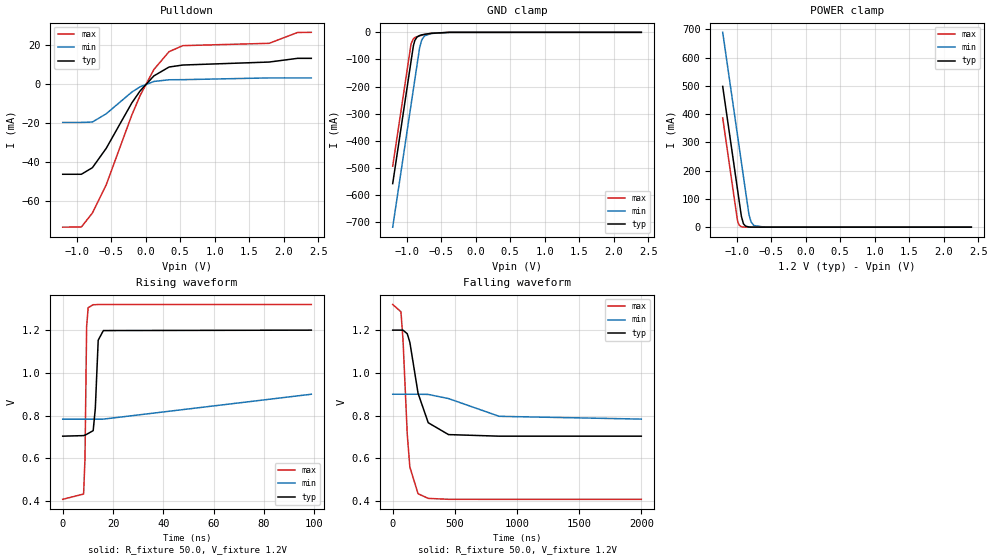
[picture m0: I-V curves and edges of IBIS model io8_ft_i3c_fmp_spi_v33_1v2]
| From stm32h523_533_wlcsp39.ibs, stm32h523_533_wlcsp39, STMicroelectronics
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[Model]   io8_ft_i3c_fmp_spi_v33_1v2
Model_type I/O_open_drain
Polarity   Non-Inverting
Enable   Active-Low
| CAP_THRESHOLD on pad IOFT is "UDTCAPC" :
| Rising=20.0% of vddiom   Falling=80.0% of vddiom
| C_comp min and max val. don't necessarily correlate with the min and max pvt
| but are the smallest and greatest pad capacitance found.
| var   typ   min   max
C_comp   3.39510pF  3.36975pF  3.42670pF
|C_comp_pulldown   3.39510pF  3.36975pF  3.42670pF
Vinl = 450.0mV
Vinh = 660.0mV
Vmeas = 600.0mV   | Reference voltage for timing measurements
Cref  = 50.0pF   | Timing specification test load capacitance value
Rref  = 1.0MOhm   | Timing specification test load resistance value
Vref  = 660.0mV   | Timing specification test load voltage
[Model Spec]
| TIME_THRESHOLD on pin ZII2CV11 is "CMOS" :
| Rising=40.0% of vdd   Falling=60.0% of vdd
Vinl 437.80000mV 335.80000mV 479.80000mV
Vinh 728.20000mV 529.20000mV 807.20000mV
| variable   typ   min   max
[Temperature Range] 25.0 125.0 -40.0
| variable   typ   min   max
[Voltage Range] 1.2V 900.0mV 1.32V
| variable   typ   min   max
[POWER Clamp Reference] 1.2V 900.0mV 1.32V
| variable   typ   min   max
[GND Clamp Reference] 0V 0V 0V
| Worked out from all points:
|   slope of the pulldown table from 0 to 0.18 V, typ, clamps not added: 30.6 ohm
|   GND clamp passes 1 mA (typ) near -0.52 V on its own axis
|   POWER clamp passes 1 mA (typ) near -0.84 V on its own axis
|   rising waveform, R_fixture 50.0, V_fixture 1.2V: 20-80 % time 1.09ns typ, 3.4ns min, 533ps max; typ from 0.704 V to 1.2 V
|   falling waveform, R_fixture 50.0, V_fixture 1.2V: 20-80 % time 103ns typ, 289ns min, 48.7ns max; typ from 1.2 V to 0.704 V
[POWER Clamp]
-1.2V     497.8mA    689.2mA    386.5mA
-990mV    140.8mA    332.2mA    29.53mA
-980mV    123.8mA    315.2mA    17.95mA
-960mV    89.81mA    281.2mA    6.634mA
-930mV    38.81mA    230.2mA    1.49mA
-900mV    12.07mA    179.2mA    334.8uA
-870mV    3.756mA    128.2mA    75.22uA
-820mV    536.4uA    44.98mA    6.246uA
-790mV    166.9uA    18.76mA    1.403uA
-750mV    35.18uA    5.846mA    191.8nA
-590mV    70.09nA    55uA       165.5pA
2.4V      0A         0A         0A
[GND Clamp]
-1.2V     -558.2mA   -719mA     -494.1mA
-940mV    -116.2mA   -277mA     -52.06mA
-930mV    -99.19mA   -260mA     -39.94mA
-900mV    -49.1mA    -209mA     -23.76mA
-880mV    -30.14mA   -175mA     -19.6mA
-850mV    -17.82mA   -124mA     -16.09mA
-810mV    -11.73mA   -56.78mA   -12.91mA
-780mV    -9.444mA   -28.21mA   -10.92mA
-740mV    -7.291mA   -13.16mA   -8.574mA
-640mV    -3.573mA   -4.171mA   -3.954mA
-380mV    -61.75uA   -230.3uA   -20.32uA
2.4V      3.863nA    718.4nA    150.6pA
| variable   typ   min   max
[Pullup Reference] 1.2V 900.0mV 1.32V
| variable   typ   min   max
[Pulldown Reference] 0V 0V 0V
[Pulldown]
-1.2V     -46.17mA   -19.61mA   -73.27mA
-930mV    -46.17mA   -19.61mA   -73.18mA
-770mV    -42.8mA    -19.4mA    -66.04mA
-570mV    -32.88mA   -15.17mA   -51.58mA
-200mV    -9.658mA   -4.081mA   -15.89mA
-80mV     -3.488mA   -1.363mA   -5.887mA
120mV     4.232mA    1.386mA    7.501mA
340mV     8.782mA    2.249mA    16.66mA
540mV     9.805mA    2.304mA    19.74mA
1.79V     11.33mA    3.204mA    20.93mA
2.2V      13.23mA    3.204mA    26.48mA
2.4V      13.23mA    3.204mA    26.56mA
[Ramp]
dV/dt_r 297.79715mV/1.03039ns 69.85238mV/3.08112ns 547.13359mV/530.98676ps
dV/dt_f 297.80466mV/100.83477ns 69.85048mV/287.77615ns 547.13918mV/47.66363ns
R_load = 50.0
| Removed startup time: 0s 0s 0s  .
| Removed end time: 98.75ns.
[Rising Waveform]
R_fixture   = 50.0
V_fixture   = 1.2V
V_fixture_min = 900.0mV
V_fixture_max = 1.32V
0s        703.7mV    783.5mV    408.1mV
8.3ns     706.4mV    783.5mV    432.8mV
8.85ns    708.8mV    783.5mV    598.1mV
9.5ns     712.4mV    783.5mV    1.216V
10.1ns    716.4mV    783.5mV    1.305V
12.1ns    729.5mV    783.5mV    1.319V
12.95ns   832.9mV    783.5mV    1.319V
14.1ns    1.153V     783.5mV    1.32V
16.15ns   1.198V     783.5mV    1.32V
98.75ns   1.2V       900mV      1.32V
| Removed startup time: 0s 0s 0s  .
| Removed end time: 1.99875us.
[Falling Waveform]
R_fixture   = 50.0
V_fixture   = 1.2V
V_fixture_min = 900.0mV
V_fixture_max = 1.32V
0s        1.2V       900mV      1.32V
66.15ns   1.2V       900mV      1.286V
82.85ns   1.2V       900mV      1.155V
117ns     1.183V     900mV      712.2mV
137.9ns   1.143V     900mV      559mV
203.9ns   904.4mV    900mV      434.4mV
285.6ns   766.6mV    899.1mV    412.5mV
448.7ns   711.1mV    879.7mV    408.2mV
856.6ns   703.7mV    796.6mV    408.1mV
1.999us   703.7mV    783.6mV    408.1mV
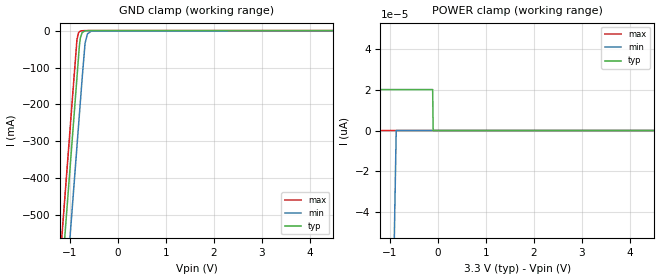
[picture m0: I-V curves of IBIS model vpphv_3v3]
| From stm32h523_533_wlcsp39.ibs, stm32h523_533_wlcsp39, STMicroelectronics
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[Model]   vpphv_3v3
Model_type Input
Polarity   Non-Inverting
Enable   Active-Low
| CAP_THRESHOLD on pad VPPHV is "UDTCAPC" :
| Rising=20.0% of vddiom   Falling=80.0% of vddiom
| C_comp min and max val. don't necessarily correlate with the min and max pvt
| but are the smallest and greatest pad capacitance found.
| var   typ   min   max
C_comp   1.80296pF  1.78284pF  1.88370pF
|C_comp_pullup   547.07000fF  538.47500fF  573.69500fF
|C_comp_pulldown   1.25589pF  1.24436pF  1.31000pF
Vinl = 810.0mV
Vinh = 2.52V
[Model Spec]
| TIME_THRESHOLD on pin ZIV11 is "CMOS" :
| Rising=40.0% of vdd   Falling=60.0% of vdd
Vinl 850.80000mV 727.80000mV 896.80000mV
Vinh 1.04820V 944.20000mV 1.06620V
| variable   typ   min   max
[Temperature Range] 25.0 125.0 -40.0
| variable   typ   min   max
[Voltage Range] 3.3V 2.7V 3.6V
| variable   typ   min   max
[POWER Clamp Reference] 3.3V 2.7V 3.6V
| variable   typ   min   max
[GND Clamp Reference] 0V 0V 0V
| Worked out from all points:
|   GND clamp passes 1 mA (typ) near -0.68 V on its own axis
[POWER Clamp]
-3.3V     7.12nA     -2.199nA   31.19nA
-2.32V    80pA       -1.816nA   5.46nA
-2.31V    40pA       -1.808nA   5.31nA
-2.3V     20pA       -1.8nA     5.17nA
-1.78V    20pA       -1.257nA   250pA
-1.73V    20pA       -1.194nA   0A
-1.02V    20pA       -209pA     0A
-900mV    20pA       -39pA      0A
-870mV    20pA       0A         0A
-110mV    20pA       0A         0A
-100mV    0A         0A         0A
6.6V      0A         0A         0A
[GND Clamp]
-3.3V     -4.293A    -4.479A    -4.189A
-1.25V    -808.1mA   -994.2mA   -703.6mA
-910mV    -230.1mA   -416.2mA   -125.6mA
-850mV    -128.1mA   -314.2mA   -25.39mA
-820mV    -77.08mA   -263.2mA   -6.741mA
-800mV    -43.08mA   -229.2mA   -3.098mA
-780mV    -20.58mA   -195.2mA   -1.572mA
-740mV    -5.162mA   -127.2mA   -481.4uA
-680mV    -904.1uA   -33.78mA   -101.4uA
-630mV    -234.3uA   -8.828mA   -46.56uA
-550mV    -27.52uA   -1.403mA   -16.23uA
6.6V      263.7nA    72.39nA    753nA
